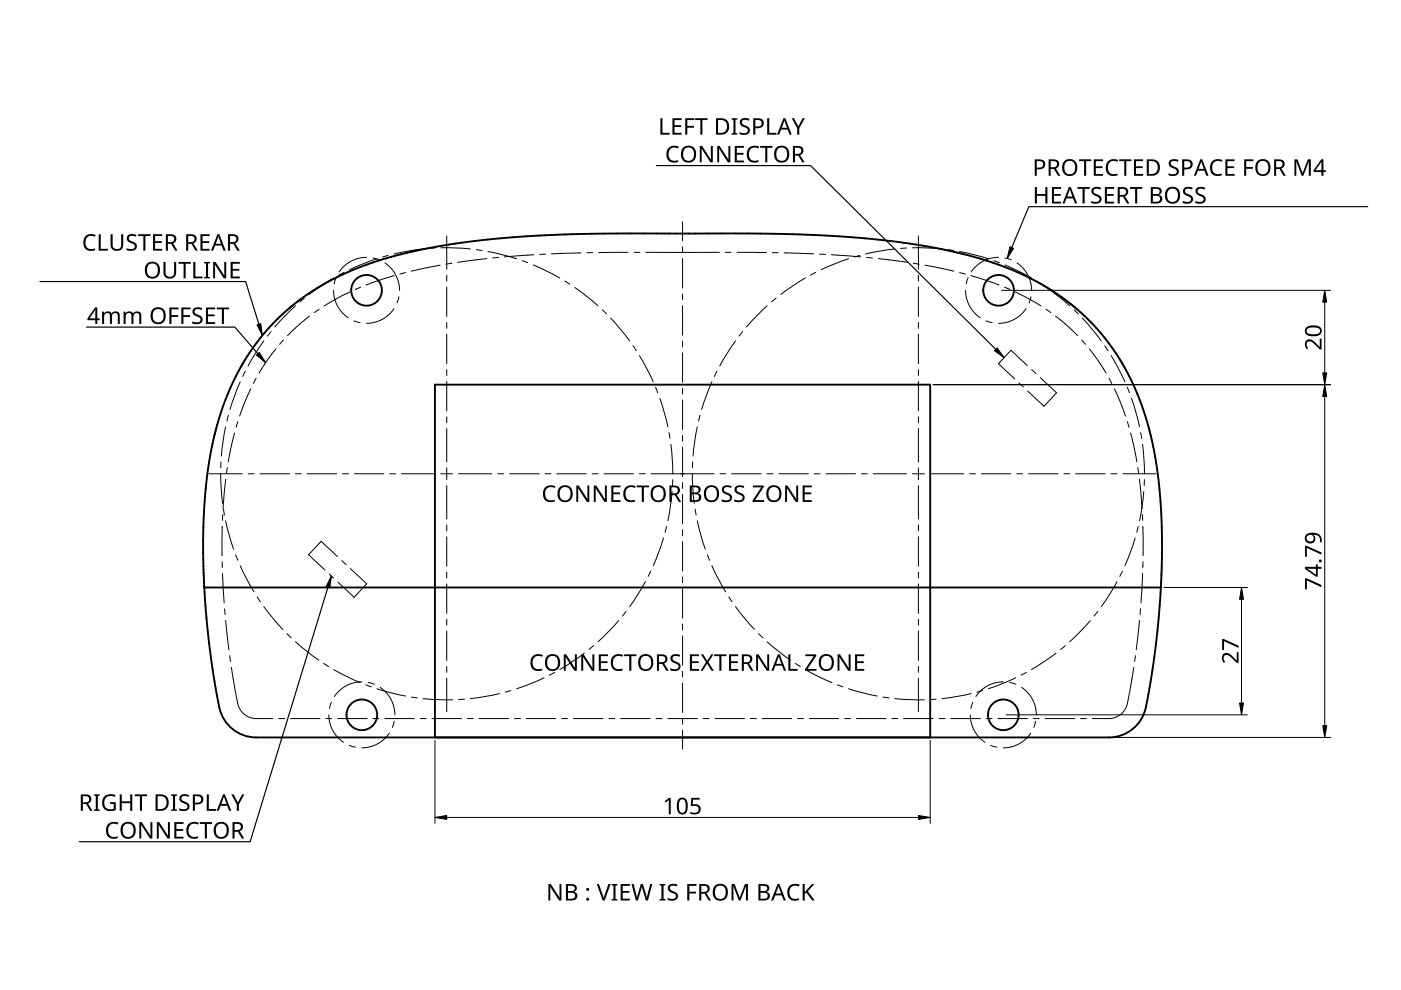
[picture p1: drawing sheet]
<svg xmlns="http://www.w3.org/2000/svg" width="297mm" height="210mm" viewBox="0 0 297 210" stroke-linecap="round" stroke-linejoin="round" font-family="sans-serif">
<g fill="none" stroke="#000" stroke-width=".21">
<path d="M70.7 58.9l-5.2 3.5M71.2 58.9l-.4 1.3M73 57.7l-1.2 .6M77.7 54.6a7 7 0 0 0-5.8 3.1M79.1 54.7l1.3 .4M79.9 54.9l-5.8 2.3M81.6 55.7a7 7 0 0 1 3.1 5.9M82.3 54.2l-1.2 .3M83.6 58.4l-6 2M86 57.8l-1.2 .3M89.7 52.8l-6.2 1M92.2 52.6l-1.2 .1"/>
<path d="M93.3 56.2l-6.1 1.3M93.5 52.5l6.2 .3M95.8 55.8l-1.3 .2M95.8 55.8h.1M101 52.9l1.2 .2M103.2 54.8l-6.2 .8M103.5 53.3l6 1.6M105.7 54.6l-1.2 .1M110.7 55.3l1.2 .4M113.1 56.2l5.6 2.7M113.2 54l-6.3 .5M115.7 53.9h-1.3"/>
<path d="M119.8 59.6l1 .7M123.2 53.6l-6.3 .2M125.7 53.6h-1.3M133.2 53.5h-6.3M134.4 53.5h1.3M136.9 53.5h15.6M155 53.5h-1.2M156.3 53.5h6.2M163.8 53.6h1.2M166.3 53.6l6.2 .2M170.8 58.9l-5.3 3.5M173 57.7l-1.2 .6"/>
<path d="M173.8 53.9h1.2M176.3 54l6.2 .5M179.9 54.9l-5.8 2.3M182.3 54.2l-1.2 .3M183.7 54.6l1.3 .1M186.2 54.8l6.2 .8M189.7 52.8l-6.2 1M192.2 52.6l-1.2 .1M193.5 52.5l6.2 .3M193.7 55.8h.1M193.7 55.8l1.2 .2M196.1 56.2l6.1 1.3"/>
<path d="M201 52.9l1.2 .2M203.5 53.3l6 1.6M203.5 57.8l1.2 .3M205.3 58.9l-.4 1.3M205.9 58.4l5.9 2M210.7 55.3l1.2 .4M211.7 54.6a7 7 0 0 0-5.8 3.1M213.1 56.2l5.6 2.7M213.1 54.7l1.3 .4M215.6 55.7a7 7 0 0 1 3.1 5.9M219.8 59.6l1 .7M52 78.7l-.5 1.1"/>
<path d="M55.9 72.3l-3.3 5.3M57.5 70.3l-.8 1M58.5 74l-1.8 2.3-1.8 2.8M60.1 72.1l-.8 .9M62.6 64.8l-4.3 4.5M64.6 63.2l-1 .8M65.6 67l-2.5 2.1-2.1 2.1M67.7 65.6l-1.1 .7M70.7 61.6a7 7 0 0 0 3.1 5.8M74.2 61.9l-5.5 3M75 68l1.3 .4M76.5 60.9l-1.2 .5"/>
<path d="M83.5 65.4a7 7 0 0 1-5.8 3.2M84.6 62.9l-.4 1.3M121.9 61l4.9 3.8M127.7 65.7l.9 .9M129.5 67.5l4 4.8M134.2 73.3l.7 1M135.6 75.4l2.9 5.6M152 78.7l-.5 1.1M155.9 72.3l-3.3 5.3M157.5 70.3l-.8 1M162.6 64.8l-4.3 4.5M164.6 63.2l-1 .8"/>
<path d="M204.7 61.6a7 7 0 0 0 3.1 5.8M209 68l1.4 .4M213 60.9l1.1 .5M215.2 61.9l5.5 3M217.5 65.4a7 7 0 0 1-5.8 3.2M217.8 77.5l-3.5-3.2-2.6 2.8 3.4 3.2M218.6 62.9l-.4 1.3M218.7 78.3l.9 .9M221.8 65.6l1 .7M221.9 61l4.9 3.8M223.8 67l2.5 2.1 2.2 2.1M227.7 65.7l.9 .9"/>
<path d="M229.3 72.1l.9 .9M229.5 67.5l4 4.8M231 74l1.7 2.3 1.8 2.8M234.2 73.3l.7 1M235.6 75.4l2.9 5.6M46.8 97.9v1.3M47.8 90.5l-.9 6.2M48.2 99.1l-.2 1.3M48.4 88l-.3 1.3M49.7 91.8l-1.3 6.1M50.4 89.4l-.3 1.2M50.9 81l-2.1 5.8"/>
<path d="M53.2 82.4l-2.4 5.8M54.3 80.2l-.6 1.1M139 82.1l.5 1.2M139.9 84.5l1.7 6M141.8 91.7l.3 1.3M142.2 94.2l.4 6.3M146.9 97.9l-.1 1.3M147.8 90.5l-.9 6.2M148.4 88l-.3 1.3M150.9 81l-2.1 5.8M216.1 81.2l.9 .9M220.5 80.1l3.5 3.2-2.7 2.8-3.4-3.2"/>
<path d="M235.1 80.2l.6 1.1M236.3 82.4l2.3 5.8M239 82.1l.5 1.2M239 89.4l.4 1.2M239.7 91.8l1.3 6.1M239.9 84.5l1.7 6M241.2 99.1l.2 1.3M241.8 91.7l.3 1.3M242.2 94.2l.5 6.3M46.8 100.5l.4 6.2M47.1 119.1v1.2M47.1 111.6v6.2"/>
<path d="M47.2 109.1v1.2M47.4 108l.2 1.2M47.8 110.4l1.7 6.1M47.9 101.6l-.6 6.2M50 117.6l.4 1.2M50.9 119.9l2.9 5.6M71.5 118l-3.4-3.2-2.7 2.8 3.5 3.3M72.5 118.9l.9 .8M140.7 114.1l-2.2 5.8M141.3 111.6l-.3 1.3M142.5 104.2l-.9 6.2M142.6 101.7v1.3"/>
<path d="M146.8 100.5l.4 6.2M147.4 108l.2 1.2M147.8 110.4l1.7 6.1M150 117.6l.4 1.2M150.9 119.9l3 5.6M240.7 114.1l-2.2 5.8M241.3 111.6l-.3 1.3M241.6 101.6l.5 6.2M242.2 109.1l.1 1.2M242.3 111.6l.1 6.2M242.3 119.1v1.2M242.5 104.2l-.9 6.2"/>
<path d="M242.6 101.7v1.3M47.2 121.6l.3 6.2M47.6 129.1l.1 1.2M47.8 131.6l.7 6.2M48.7 139l.2 1.3M54.5 126.6l.7 1M55.9 128.6l4 4.8M60.8 134.3l.9 .9M62.6 136.1l5 3.9M69.8 121.7l.9 .9M74.3 120.6l3.4 3.2-2.1 2.3-.5 .5-3.5-3.2M123.9 138.5l-5.2 3.5"/>
<path d="M125.8 136.9l-.9 .8M131.2 131.6l-4.4 4.5M132.7 129.6l-.7 1M136.8 123.3l-3.3 5.3M138 121.1l-.6 1.1M154.5 126.6l.7 1M155.9 128.6l4.1 4.8M160.8 134.3l.9 .9M162.6 136.1l5 3.9M223.9 138.5l-5.2 3.5M225.8 136.9l-.9 .8M231.2 131.6l-4.4 4.5"/>
<path d="M232.7 129.6l-.7 1M236.8 123.3l-3.3 5.3M238 121.1l-.6 1.1M240.7 139l-.1 1.3M241.6 131.6l-.7 6.2M241.8 129.1l-.1 1.2M242.3 121.6l-.4 6.2M49.1 141.5l1.2 6.9a4.1 4.1 0 0 0 4 4h3.5M59.1 152.4h1.2M61.6 152.4h6.2M68.6 140.7l1.1 .6M69.1 152.4h1.2"/>
<path d="M69.7 151.6a7 7 0 0 0 3.1 5.8M70.2 148.9l-.4 1.3M70.7 142l5.7 2.7M71.6 152.4h6.2M74 158l1.3 .4M76.7 144.6a7 7 0 0 0-5.8 3.1M77.5 145.2l1.2 .4M78.1 144.7l1.3 .4M79.1 152.4h1.2M79.9 146l6.1 1.6M80.6 145.7a7 7 0 0 1 3.1 5.9M81.6 152.4h6.2"/>
<path d="M82.5 155.5a7 7 0 0 1-5.8 3.1M83.6 152.9l-.4 1.3M87.2 147.8l1.3 .2M89.1 152.4h1.2M89.7 148.1l6.3 .3M91.6 152.4h6.2M98.5 148.2l-1.3 .1M99.1 152.4h1.2M101.6 152.4h6.2M105.9 147.1l-6.2 1M108.3 146.4l-1.2 .4M109.1 152.4h1.2"/>
<path d="M111.6 152.4h6.2M115.4 143.7l-5.9 2.3M117.6 142.6l-1.1 .6M119.1 152.4h1.2M121.6 152.4h6.2M129.1 152.4h1.2M131.6 152.4h6.2M139.1 152.4h1.2M141.6 152.4h6.2M149.1 152.4h1.2M151.6 152.4h6.2M159.1 152.4h1.2"/>
<path d="M161.6 152.4h6.2M168.6 140.7l1.1 .6M169.1 152.4h1.2M170.8 142l5.6 2.7M171.6 152.4h6.2M177.5 145.2l1.2 .4M179.1 152.4h1.2M179.9 146l6.1 1.6M181.6 152.4h6.2M187.2 147.8l1.3 .2M189.1 152.4h1.2M189.7 148.1l6.3 .3"/>
<path d="M191.6 152.4h6.2M198.5 148.2l-1.3 .1M199.1 152.4h1.2M201.6 152.4h6.2M205.7 151.6a7 7 0 0 0 3.1 5.8M205.9 147.1l-6.2 1M206.3 148.9l-.4 1.3M208.3 146.4l-1.2 .4M209.1 152.4h1.2M210 158l1.4 .4M211.6 152.4h6.2M212.7 144.6a7 7 0 0 0-5.8 3.1"/>
<path d="M214.1 144.7l1.3 .4M215.4 143.7l-5.9 2.3M216.6 145.7a7 7 0 0 1 3.1 5.9M217.6 142.6l-1.1 .6M218.5 155.5a7 7 0 0 1-5.8 3.1M219.1 152.4h1.2M219.6 152.9l-.4 1.3M221.6 152.4h6.2M229.1 152.4h1.2M240.4 141.5l-1.2 6.9a4.1 4.1 0 0 1-4.1 4h-3.5"/>
</g>
<g fill="none" stroke="#000" stroke-width=".4">
<path d="M245.3 99.5l-.7-4.3-1-4.2-1.1-3.9-1.4-3.6-1.6-3.6-1.9-3.3-2-3.1-2.3-3-2.6-2.7-2.6-2.5-2.9-2.2-3.2-2.1-3.3-1.9-3.7-1.7-3.6-1.4-4.3-1.4-4.4-1.1-5-1.1-11-1.5-12.3-1-14.8-.4h-31.5l-14.9 .5-7.7 .6-7.1 .8-6.7 1-6.1 1.4-6.6 1.9-6.1 2.4-5.5 2.9-4.8 3.3-4.4 4-3.8 4.4-3.2 4.9-2.8 5.6-2.1 6.2-1.6 6.4-1 7.2-.5 7.7-.1 9 .5 9.7 1.1 9.8 1.5 9.1a8.4 8.4 0 0 0 8.1 8.1l181.8-.1a8.4 8.4 0 0 0 7.2-8l1.1-6.4 .8-6.5 .6-6.6 .4-6.2 .2-6.3-.1-6.2-.4-5.4-.6-5.2M43.3 124.6h202.8M92.2 156.4v-74.8h105v74.8"/>
<circle cx="77.7" cy="61.6" r="3.3"/>
<circle cx="211.7" cy="61.6" r="3.3"/>
<circle cx="76.7" cy="151.6" r="3.3"/>
<circle cx="212.7" cy="151.6" r="3.3"/>
</g>
<g fill="#000">
<path d="M140 25.1h.5v3.1h1.5v.4h-2zM141.7 31.4a1.95 1.95 0 0 1 2.2-.3l-.1 .4a1.36 1.36 0 0 0-1.7 .1 1.36 1.36 0 0 0-.3 1.7 1.32 1.32 0 0 0 2 .7v.3a1.77 1.77 0 0 1-2.1-.3 1.77 1.77 0 0 1-.3-2.1zM142.6 25.1h1.9v.4h-1.5v1h1.4v.4h-1.4v1.3h1.5v.4h-1.9zM145.3 25.1h1.9v.4h-1.5v1.2h1.4v.4h-1.4v1.5h-.4zM147.4 25.1h2.6v.4h-1.1v3.1h-.4v-3.1h-1.1zM148.4 30.9h.5l1.8 2.9v-2.9h.4v3.5h-.5l-1.9-2.9 .1 2.9h-.4zM152.1 30.9h.5l1.8 2.9v-2.9h.4v3.5h-.5l-1.8-2.9v2.9h-.4zM155.1 25.1h1.3v.2l-.5 .1v2.8l.5 .1v.3h-1.3v-.3l.4-.1v-2.8l-.4-.1zM155.8 30.9h1.9v.4h-1.5v1.1h1.4v.4h-1.4v1.2h1.5v.4h-1.9zM157 25.4a1.65 1.65 0 0 1 1.9-.2l-.1 .4a1.01 1.01 0 0 0-1.5 .2 1.32 1.32 0 0 0 1.2 1 .97 .97 0 0 1 .4 1.3 .97 .97 0 0 1-1.1 .5l-1-.2v-.4a1.24 1.24 0 0 0 1.8-.2 1.06 1.06 0 0 0-1.1-.9 .95 .95 0 0 1-.5-1.5zM158.8 31.4a1.95 1.95 0 0 1 2.2-.3l-.2 .4a1.36 1.36 0 0 0-1.7 .1 1.36 1.36 0 0 0-.2 1.7 1.32 1.32 0 0 0 1.9 .7v.3a1.77 1.77 0 0 1-2.1-.3 1.77 1.77 0 0 1-.3-2.1zM162.7 25.1h.4v3.1h1.5v.4h-1.9z"/>
<path d="M161.2 30.9h2.6v.4h-1.1v3.1h-.5v-3.1h-1zM167.9 25.1h.4l.9 1.7 1-1.7h.4l-1.1 2.1v1.4h-.5v-1.4zM228.8 33.8h2.6v.4h-1.1v3.1h-.5v-3.1h-1zM231.9 33.8h1.9v.4h-1.5v1.1h1.5v.3h-1.5v1.3h1.5v.4h-1.9zM234.9 34.2a1.95 1.95 0 0 1 2.2-.3l-.2 .4a1.36 1.36 0 0 0-1.7 .2 1.36 1.36 0 0 0-.2 1.6 1.32 1.32 0 0 0 1.9 .7v.4a1.77 1.77 0 0 1-2-.3 1.77 1.77 0 0 1-.3-2.1zM237.3 33.8h2.6v.4h-1.1v3.1h-.4v-3.1h-1.1zM240.4 33.8h2v.4h-1.5v1.1h1.4v.3h-1.4v1.3h1.5v.4h-2zM248 34.1a1.65 1.65 0 0 1 1.9-.2l-.2 .4a1.01 1.01 0 0 0-1.5 .2 1.31 1.31 0 0 0 1.3 1 .97 .97 0 0 1 .4 1.3 .97 .97 0 0 1-1.2 .5l-1-.1v-.5a1.24 1.24 0 0 0 1.8-.2 1.06 1.06 0 0 0-1-.9 .95 .95 0 0 1-.5-1.5zM257 34.2a1.95 1.95 0 0 1 2.2-.3l-.2 .4a1.36 1.36 0 0 0-1.7 .2 1.36 1.36 0 0 0-.2 1.6 1.32 1.32 0 0 0 1.9 .7v.4a1.77 1.77 0 0 1-2-.3 1.77 1.77 0 0 1-.3-2.1zM259.8 33.8h2v.4h-1.6v1.1h1.5v.3h-1.5v1.3h1.6v.4h-2zM263.8 33.8h1.9v.4h-1.5v1.2h1.4v.4h-1.4v1.5h-.4zM274.4 33.8h.7l1.1 2.8 1.1-2.8h.6v3.5h-.4v-3.1l-1.2 3.1h-.3l-1.2-3.1v3.1h-.4z"/>
<path d="M18.1 50.1a1.95 1.95 0 0 1 2.2-.3l-.2 .4a1.36 1.36 0 0 0-1.7 .1 1.36 1.36 0 0 0-.2 1.7 1.32 1.32 0 0 0 2 .7v.4a1.77 1.77 0 0 1-2.1-.4 1.77 1.77 0 0 1-.3-2zM20.9 49.7h.5v3.1h1.5v.3h-2zM23.4 49.7h.5v2.2a.9 .9 0 0 0 .9 .9 .9 .9 0 0 0 .9-.9v-2.2h.4v2.2a1.34 1.34 0 0 1-1.3 1.3 1.34 1.34 0 0 1-1.4-1.3zM27 50a1.65 1.65 0 0 1 1.9-.2l-.1 .4a1.01 1.01 0 0 0-1.5 .2 1.31 1.31 0 0 0 1.2 1 .97 .97 0 0 1 .4 1.2 .97 .97 0 0 1-1.1 .6l-1-.2v-.4a1.24 1.24 0 0 0 1.8-.2 1.06 1.06 0 0 0-1.1-1 .95 .95 0 0 1-.5-1.4zM29.3 49.7h2.6v.3h-1.1v3.1h-.4v-3.1h-1.1zM32.4 49.7h2v.3h-1.5v1.1h1.4v.4h-1.4v1.3h1.5v.3h-2zM34.7 55.5h.4v2.3a.9 .9 0 0 0 .9 .9 .9 .9 0 0 0 .9-.9v-2.3h.4v2.3a1.35 1.35 0 0 1-1.3 1.3 1.35 1.35 0 0 1-1.3-1.3zM37.8 55.5h2.7v.4h-1.1v3.1h-.5v-3.1h-1.1zM41 55.5h.4v3.1h1.5v.4h-1.9zM42.5 49.7h1.9v.3h-1.5v1.1h1.5v.4h-1.5v1.3h1.5v.3h-1.9zM43.3 55.5h1.2v.3l-.4 .1v2.8l.4 .1v.2h-1.2v-.2l.4-.1v-2.8l-.4-.1zM45.2 55.5h.5l1.9 2.9-.1-2.9h.5v3.5h-.6l-1.8-2.9v2.9h-.4z"/>
<path d="M48.9 55.5h2v.4h-1.6v1.1h1.5v.4h-1.5v1.2h1.6v.4h-2zM219.4 39.7h.4v1.4h1.8v-1.4h.5v3.4h-.5v-1.6h-1.8v1.6h-.4zM223 39.7h2v.3h-1.5v1.1h1.4v.4h-1.4v1.3h1.5v.3h-2zM228.4 39.7h2.6v.3h-1v3.1h-.5v-3.1h-1.1zM231.6 40a1.65 1.65 0 0 1 1.9-.2l-.2 .4a1.01 1.01 0 0 0-1.5 .2 1.31 1.31 0 0 0 1.3 1 .97 .97 0 0 1 .4 1.2 .97 .97 0 0 1-1.2 .6l-1-.2v-.4a1.24 1.24 0 0 0 1.8-.2 1.06 1.06 0 0 0-1-1 .95 .95 0 0 1-.5-1.4zM234.3 39.7h1.9v.3h-1.5v1.1h1.4v.4h-1.4v1.3h1.5v.3h-1.9zM239.6 39.7h2.6v.3h-1.1v3.1h-.4v-3.1h-1.1zM251 40a1.65 1.65 0 0 1 1.9-.2l-.2 .4a1.01 1.01 0 0 0-1.4 .2 1.31 1.31 0 0 0 1.2 1 .97 .97 0 0 1 .4 1.2 .97 .97 0 0 1-1.2 .6l-.9-.2v-.4a1.24 1.24 0 0 0 1.7-.2 1.06 1.06 0 0 0-1-1 .95 .95 0 0 1-.5-1.4zM253.7 40a1.65 1.65 0 0 1 1.9-.2l-.2 .4a1.01 1.01 0 0 0-1.5 .2 1.31 1.31 0 0 0 1.3 1 .97 .97 0 0 1 .4 1.2 .97 .97 0 0 1-1.2 .6l-1-.2v-.4a1.24 1.24 0 0 0 1.8-.2 1.06 1.06 0 0 0-1-1 .95 .95 0 0 1-.5-1.4zM21.6 66.1h.4l.1 .3a.99 .99 0 0 1 1.6 .1 .93 .93 0 0 1 1-.4 .93 .93 0 0 1 .7 .9v1.7h-.4v-1.7a.64 .64 0 0 0-.8-.6 .64 .64 0 0 0-.5 .8v1.5h-.4v-1.7a.66 .66 0 0 0-.8-.6 .66 .66 0 0 0-.4 .9v1.4h-.5zM26.2 66.1h.4v.3a.99 .99 0 0 1 1.6 .1 .93 .93 0 0 1 1.1-.4 .93 .93 0 0 1 .7 .9v1.7h-.5v-1.7a.64 .64 0 0 0-.7-.6 .64 .64 0 0 0-.5 .8v1.5h-.4v-1.7a.66 .66 0 0 0-.9-.6 .66 .66 0 0 0-.4 .9v1.4h-.4zM35.9 65.2h2v.4h-1.5v1.2h1.4v.4h-1.4v1.5h-.5z"/>
<path d="M38.4 65.2h2v.4h-1.5v1.2h1.4v.4h-1.4v1.5h-.5zM41 65.5a1.65 1.65 0 0 1 1.9-.2l-.2 .4a1.01 1.01 0 0 0-1.4 .2 1.31 1.31 0 0 0 1.2 1.1 .97 .97 0 0 1 .4 1.2 .97 .97 0 0 1-1.2 .5l-.9-.1v-.5a1.24 1.24 0 0 0 1.7-.2 1.06 1.06 0 0 0-1-.9 .95 .95 0 0 1-.5-1.5zM43.7 65.2h1.9v.4h-1.5v1.1h1.4v.4h-1.4v1.2h1.5v.4h-1.9zM46 65.2h2.6v.4h-1.1v3.1h-.5v-3.1h-1zM276.9 72.2a1.5 1.5 0 0 1 2.2 .6l.7 .8v-1.8h.4v2.3h-.4l-1.1-1.1a.98 .98 0 0 0-1.6-.3l-.1 .5 .4 .6-.3 .3a1.47 1.47 0 0 1-.2-1.9zM115.6 103.4a1.95 1.95 0 0 1 2.1-.3l-.1 .4a1.36 1.36 0 0 0-1.7 .1 1.36 1.36 0 0 0-.2 1.7 1.32 1.32 0 0 0 1.9 .6v.4a1.77 1.77 0 0 1-2.1-.3 1.77 1.77 0 0 1-.3-2.1zM122.2 102.9h.5l1.9 2.9-.1-2.9h.4v3.5h-.5l-1.8-2.9v2.9h-.4zM125.9 102.9h.5l1.9 2.9-.1-2.9h.5v3.5h-.6l-1.8-2.9v2.9h-.4zM129.6 102.9h2v.4h-1.6v1.1h1.5v.4h-1.5v1.2h1.6v.4h-2zM132.6 103.4a1.95 1.95 0 0 1 2.2-.3l-.2 .4a1.36 1.36 0 0 0-1.7 .1 1.36 1.36 0 0 0-.2 1.7 1.32 1.32 0 0 0 1.9 .6v.4a1.77 1.77 0 0 1-2-.3 1.77 1.77 0 0 1-.3-2.1zM135 102.9h2.6v.4h-1.1v3.1h-.4v-3.1h-1.1zM153.2 103.3a1.65 1.65 0 0 1 1.9-.2l-.1 .4a1.01 1.01 0 0 0-1.5 .2 1.31 1.31 0 0 0 1.2 1 .97 .97 0 0 1 .4 1.2 .97 .97 0 0 1-1.1 .6l-1-.2v-.4a1.24 1.24 0 0 0 1.8-.2 1.06 1.06 0 0 0-1.1-1 .95 .95 0 0 1-.5-1.4z"/>
<path d="M155.9 103.3a1.65 1.65 0 0 1 1.9-.2l-.1 .4a1.01 1.01 0 0 0-1.5 .2 1.31 1.31 0 0 0 1.2 1 .97 .97 0 0 1 .4 1.2 .97 .97 0 0 1-1.2 .6l-.9-.2v-.4a1.24 1.24 0 0 0 1.7-.2 1.06 1.06 0 0 0-1-1 .95 .95 0 0 1-.5-1.4zM159.6 102.9h2.3v.4l-1.8 2.7h1.9v.4h-2.4v-.3l1.8-2.8h-1.8zM166.5 102.9h.5l1.8 2.9v-2.9h.4v3.5h-.5l-1.9-2.9 .1 2.9h-.4zM170.2 102.9h1.9v.4h-1.5v1.1h1.4v.4h-1.4v1.2h1.5v.4h-1.9zM276.7 115.7h.3l3.2 1.4v.5l-3.1-1.4v1.9h-.4zM112.9 139.2a1.95 1.95 0 0 1 2.2-.3l-.2 .4a1.36 1.36 0 0 0-1.7 .1 1.36 1.36 0 0 0-.2 1.7 1.32 1.32 0 0 0 2 .6v.4a1.77 1.77 0 0 1-2.1-.3 1.77 1.77 0 0 1-.3-2.1zM129.9 139.2a1.95 1.95 0 0 1 2.2-.3l-.1 .4a1.36 1.36 0 0 0-1.7 .1 1.36 1.36 0 0 0-.3 1.7 1.32 1.32 0 0 0 2 .6v.4a1.77 1.77 0 0 1-2.1-.3 1.77 1.77 0 0 1-.3-2.1zM259.3 138.7a1.5 1.5 0 0 1 2.2 .6l.7 .7v-1.7h.4v2.3h-.4l-1.1-1.1a.98 .98 0 0 0-1.6-.3v.5l.3 .6-.3 .3a1.47 1.47 0 0 1-.2-1.9zM259.1 135.5h.3l3.2 1.4v.5l-3.1-1.5v1.9h-.4zM276.7 122.6h.3l3.2 1.4v.5l-3.1-1.4v1.8h-.4zM119.5 138.7h.5l1.9 2.9v-2.9h.4v3.5h-.5l-1.9-2.9v2.9h-.4zM123.2 138.7h.6l1.8 2.9v-2.9h.4v3.5h-.5l-1.9-2.9 .1 2.9h-.5z"/>
<path d="M127 138.7h1.9v.4h-1.5v1.1h1.4v.4h-1.4v1.2h1.5v.4h-1.9zM132.3 138.7h2.6v.4h-1v3.1h-.5v-3.1h-1.1zM142.3 139.1a1.65 1.65 0 0 1 1.9-.2l-.1 .4a1.01 1.01 0 0 0-1.5 .2 1.31 1.31 0 0 0 1.2 1 .97 .97 0 0 1 .4 1.2 .97 .97 0 0 1-1.1 .6l-1-.2v-.4a1.24 1.24 0 0 0 1.7-.3 1.06 1.06 0 0 0-1-.9 .95 .95 0 0 1-.5-1.4zM146.3 138.7h1.9v.4h-1.5v1.1h1.4v.4h-1.4v1.2h1.5v.4h-1.9zM148.6 138.7h.5l.8 1.4 .9-1.4h.5l-1.1 1.7 1.2 1.8h-.5l-1-1.5-.9 1.5h-.5l1.2-1.8zM151.4 138.7h2.6v.4h-1v3.1h-.5v-3.1h-1.1zM154.6 138.7h1.9v.4h-1.5v1.1h1.4v.4h-1.4v1.2h1.5v.4h-1.9zM160.3 138.7h.5l1.9 2.9v-2.9h.4v3.5h-.5l-1.9-2.9v2.9h-.4zM167.1 138.7h.5v3.1h1.5v.4h-2zM170.7 138.7h2.4v.4l-1.9 2.7h1.9v.4h-2.4v-.3l1.8-2.8h-1.8zM177.6 138.7h.5l1.8 2.9v-2.9h.4v3.5h-.5l-1.8-2.9v2.9h-.4zM181.3 138.7h1.9v.4h-1.5v1.1h1.4v.4h-1.4v1.2h1.5v.4h-1.9z"/>
<path d="M19.9 168.4h1.3v.3l-.5 .1v2.8l.5 .1v.2h-1.3v-.2l.4-.1v-2.8l-.4-.1zM22.1 168.9a2.23 2.23 0 0 1 2.4-.3l-.2 .4a1.44 1.44 0 0 0-2.2 1 1.44 1.44 0 0 0 2 1.5v-1h-.8v-.4h1.2v1.7l-.2 .1a1.86 1.86 0 0 1-2.4-.6 1.86 1.86 0 0 1 .2-2.4zM22.9 174.7a1.95 1.95 0 0 1 2.2-.2l-.2 .3a1.36 1.36 0 0 0-1.6 .2 1.36 1.36 0 0 0-.3 1.6 1.32 1.32 0 0 0 2 .7v.4a1.77 1.77 0 0 1-2.1-.3 1.77 1.77 0 0 1-.3-2.1zM25.4 168.4h.4v1.5h1.8v-1.5h.4v3.5h-.4v-1.6h-1.8v1.6h-.4zM28.6 168.4h2.6v.4h-1.1v3.1h-.4v-3.1h-1.1zM29.5 174.3h.6l1.8 2.9v-2.9h.4v3.5h-.5l-1.9-2.9v2.9h-.4zM33.3 174.3h.5l1.8 2.9v-2.9h.4v3.5h-.5l-1.9-2.9 .1 2.9h-.4zM36.3 168.4h1.2v.3l-.4 .1v2.8l.4 .1v.2h-1.2v-.2l.4-.1v-2.8l-.4-.1zM37 174.3h1.9v.4h-1.5v1.1h1.4v.4h-1.4v1.2h1.5v.4h-1.9zM38.2 168.8a1.65 1.65 0 0 1 1.9-.2l-.1 .4a1.01 1.01 0 0 0-1.5 .2 1.31 1.31 0 0 0 1.2 1 .97 .97 0 0 1 .4 1.2 .97 .97 0 0 1-1.2 .6l-.9-.2v-.4a1.24 1.24 0 0 0 1.7-.3 1.06 1.06 0 0 0-1-.9 .95 .95 0 0 1-.5-1.4zM39.9 174.7a1.95 1.95 0 0 1 2.2-.2l-.1 .3a1.36 1.36 0 0 0-1.7 .2 1.36 1.36 0 0 0-.3 1.6 1.32 1.32 0 0 0 2 .7v.4a1.77 1.77 0 0 1-2.1-.3 1.77 1.77 0 0 1-.3-2.1zM43.8 168.4h.5v3.1h1.5v.4h-2z"/>
<path d="M42.3 174.3h2.7v.4h-1.1v3.1h-.5v-3.1h-1.1zM49 168.4h.5l.9 1.7 .9-1.7h.5l-1.2 2.2v1.3h-.4v-1.3zM140.9 169.9l1-.7h.3v3.4h-.4v-3l-.7 .6zM146.6 169.2h1.7v.4h-1.4v1a1.17 1.17 0 0 1 1.7 .9 1.17 1.17 0 0 1-1.6 1.2l-.6-.2v-.4a1.03 1.03 0 0 0 1 .3 1.03 1.03 0 0 0 .7-.8 .93 .93 0 0 0-1.4-.7l-.3-.1zM116.3 187.4h.5l1.8 2.9v-2.9h.4v3.5h-.5l-1.8-2.9v2.9h-.4zM126.5 187.4h.5l1 3 1-3h.5l-1.3 3.5h-.4zM129.7 187.4h1.2v.3l-.4 .1v2.8l.4 .1v.2h-1.2v-.2l.4-.1v-2.8l-.4-.1zM131.6 187.4h1.9v.4h-1.5v1.1h1.4v.4h-1.4v1.2h1.5v.4h-1.9zM133.9 187.4h.4l.8 3 .8-3h.4l.8 3 .7-3h.5l-.9 3.5h-.5l-.8-3-.8 3h-.5zM139.8 187.4h1.3v.3l-.4 .1v2.8l.4 .1v.2h-1.3v-.2l.4-.1v-2.8l-.4-.1zM141.8 187.8a1.65 1.65 0 0 1 1.9-.2l-.2 .4a1.01 1.01 0 0 0-1.5 .2 1.31 1.31 0 0 0 1.3 1 .97 .97 0 0 1 .4 1.2 .97 .97 0 0 1-1.2 .6l-1-.2v-.4a1.24 1.24 0 0 0 1.8-.2 1.06 1.06 0 0 0-1-1 .95 .95 0 0 1-.5-1.4zM145.7 187.4h2v.4h-1.5v1.3h1.4v.3h-1.4v1.5h-.5z"/>
<path d="M155.1 187.4h.6l1.1 2.9 1.1-2.9h.7v3.5h-.5l.1-3-1.2 3h-.4l-1.1-3v3h-.4zM167.4 187.9a1.95 1.95 0 0 1 2.2-.3l-.2 .4a1.36 1.36 0 0 0-1.7 .1 1.36 1.36 0 0 0-.2 1.7 1.32 1.32 0 0 0 1.9 .6v.4a1.77 1.77 0 0 1-2.1-.3 1.77 1.77 0 0 1-.3-2.1zM170.2 187.4h.4v1.8l1.6-1.8h.5l-1.4 1.6 1.4 1.9h-.5l-1.2-1.6-.4 .3v1.3h-.4z"/>
<path d="M144.8 31.4a1.7 1.7 0 0 1 2.2-.2 1.7 1.7 0 0 1 .5 2.1 1.64 1.64 0 0 1-2 1.1 1.64 1.64 0 0 1-1.1-2.1zM145.2 31.6a1.56 1.56 0 0 0 .5 2.5 1.35 1.35 0 0 0 1.3-.6 1.35 1.35 0 0 0 .1-1.4 1.14 1.14 0 0 0-1.9-.5z"/>
<path d="M151.8 25.1h1.1a1.74 1.74 0 0 1 1.7 1.8 1.74 1.74 0 0 1-1.8 1.7h-1zM152.2 25.4v2.8h.5a1.37 1.37 0 0 0 1.4-1.3 1.37 1.37 0 0 0-1.3-1.5z"/>
<path d="M159.7 25.1h.9a1.1 1.1 0 0 1 1.3 1.1 1.1 1.1 0 0 1-1.4 1h-.4v1.4h-.4zM160.1 25.4v1.4a.94 .94 0 0 0 1.4-.7 .7 .7 0 0 0-.9-.7z"/>
<path d="M164.5 31.4a1.7 1.7 0 0 1 2.2-.2 1.7 1.7 0 0 1 .6 2.1 1.64 1.64 0 0 1-2.1 1.1 1.64 1.64 0 0 1-1-2.1zM165 31.6a1.56 1.56 0 0 0 .5 2.5 1.35 1.35 0 0 0 1.3-.6 1.35 1.35 0 0 0 0-1.4 1.14 1.14 0 0 0-1.8-.5z"/>
<path d="M166.1 25.1h.4l1.4 3.5h-.5l-.4-1.1h-1.4l-.4 1.1h-.5zM166.3 25.5l-.6 1.6h1.2z"/>
<path d="M168.1 30.9h1a1 1 0 0 1 1.2 .7 1 1 0 0 1-.7 1.3l1 1.5h-.5l-.9-1.4h-.6v1.4h-.5zM168.6 31.3v1.3h.5a.67 .67 0 0 0 .8-.6 .67 .67 0 0 0-.8-.7z"/>
<path d="M219.4 33.8h.9a1.1 1.1 0 0 1 1.3 1.1 1.1 1.1 0 0 1-1.4 1h-.4v1.4h-.4zM219.8 34.2v1.3a.94 .94 0 0 0 1.4-.7 .7 .7 0 0 0-.9-.6z"/>
<path d="M222.3 33.8h1a1 1 0 0 1 1.2 .7 1 1 0 0 1-.6 1.2l.9 1.6h-.5l-.8-1.5h-.7v1.5h-.5zM222.8 34.2v1.3h.5a.67 .67 0 0 0 .8-.7 .67 .67 0 0 0-.8-.6z"/>
<path d="M225.6 34.2a1.7 1.7 0 0 1 2.2-.2 1.7 1.7 0 0 1 .6 2.1 1.64 1.64 0 0 1-2.1 1.1 1.64 1.64 0 0 1-1.1-2.1zM226 34.4a1.56 1.56 0 0 0 .5 2.5 1.35 1.35 0 0 0 1.3-.6 1.35 1.35 0 0 0 .1-1.4 1.14 1.14 0 0 0-1.9-.5z"/>
<path d="M244 39.7h1a.94 .94 0 0 1 1 .2 .94 .94 0 0 1 .2 1l-.6 .4a.95 .95 0 0 1 .8 1.2 .95 .95 0 0 1-1.2 .6h-1.2zM244.4 41.5v1.3h.7a.66 .66 0 0 0 .9-.7 .66 .66 0 0 0-.9-.6zM244.4 40v1.1h.7a.6 .6 0 0 0 .8-.6 .6 .6 0 0 0-.9-.5z"/>
<path d="M243.1 33.8h1.1a1.74 1.74 0 0 1 1.7 1.8 1.74 1.74 0 0 1-1.8 1.7h-1zM243.6 34.2v2.7h.4a1.37 1.37 0 0 0 1.5-1.3 1.37 1.37 0 0 0-1.4-1.4z"/>
<path d="M250.6 33.8h1a1.1 1.1 0 0 1 1.3 1.1 1.1 1.1 0 0 1-1.4 1h-.4v1.4h-.5zM251.1 34.2v1.3a.94 .94 0 0 0 1.3-.7 .7 .7 0 0 0-.9-.6z"/>
<path d="M254.5 33.8h.4l1.3 3.5h-.4l-.4-1.1h-1.4l-.4 1.1h-.5zM254.7 34.2l-.6 1.6h1.1z"/>
<path d="M266.6 34.2a1.7 1.7 0 0 1 2.1-.2 1.7 1.7 0 0 1 .6 2.1 1.64 1.64 0 0 1-2.1 1.1 1.64 1.64 0 0 1-1-2.1zM267 34.4a1.56 1.56 0 0 0 .5 2.5 1.35 1.35 0 0 0 1.3-.6 1.35 1.35 0 0 0 0-1.4 1.14 1.14 0 0 0-1.8-.5z"/>
<path d="M270.1 33.8h1a1 1 0 0 1 1.2 .7 1 1 0 0 1-.6 1.2l.9 1.6h-.5l-.8-1.5h-.7v1.5h-.5zM270.6 34.2v1.3h.5a.67 .67 0 0 0 .8-.7 .67 .67 0 0 0-.8-.6z"/>
<path d="M280.1 33.8h.5v2.3h.5v.4h-.5v.8h-.4v-.8h-1.7v-.4zM280.2 34.2l-1.3 1.9h1.3z"/>
<path d="M31.1 56a1.7 1.7 0 0 1 2.2-.2 1.7 1.7 0 0 1 .6 2.1 1.64 1.64 0 0 1-2.1 1.1 1.64 1.64 0 0 1-1.1-2.1zM31.5 56.1a1.56 1.56 0 0 0 .6 2.6 1.35 1.35 0 0 0 1.2-.6 1.35 1.35 0 0 0 .1-1.4 1.14 1.14 0 0 0-1.9-.6z"/>
<path d="M35.2 49.7h.9a1 1 0 0 1 1.2 .6 1 1 0 0 1-.6 1.3l.9 1.5h-.5l-.8-1.4h-.7v1.4h-.4zM35.6 50v1.3h.5a.67 .67 0 0 0 .8-.6 .67 .67 0 0 0-.8-.7z"/>
<path d="M39.5 49.7h.9a1 1 0 0 1 1.3 .6 1 1 0 0 1-.7 1.3l1 1.5h-.6l-.8-1.4h-.7v1.4h-.4zM39.9 50v1.3h.5a.67 .67 0 0 0 .8-.6 .67 .67 0 0 0-.8-.7z"/>
<path d="M46.1 49.6h.4l1.4 3.5h-.5l-.4-1h-1.4l-.4 1h-.5zM46.3 50.1l-.6 1.6h1.2z"/>
<path d="M48.3 49.7h1a1 1 0 0 1 1.2 .6 1 1 0 0 1-.6 1.3l.9 1.5h-.5l-.8-1.4h-.7v1.4h-.5zM48.8 50v1.3h.5a.67 .67 0 0 0 .8-.6 .67 .67 0 0 0-.8-.7z"/>
<path d="M226.6 39.6h.4l1.4 3.5h-.5l-.4-1h-1.4l-.4 1h-.4zM226.8 40.1l-.5 1.6h1.1z"/>
<path d="M237 39.7h.9a1 1 0 0 1 1.3 .6 1 1 0 0 1-.7 1.3l1 1.5h-.6l-.8-1.4h-.7v1.4h-.4zM237.4 40v1.3h.5a.67 .67 0 0 0 .8-.6 .67 .67 0 0 0-.8-.7z"/>
<path d="M247.4 40.1a1.7 1.7 0 0 1 2.2-.2 1.7 1.7 0 0 1 .5 2.1 1.64 1.64 0 0 1-2 1.1 1.64 1.64 0 0 1-1.1-2.1zM247.8 40.3a1.56 1.56 0 0 0 .5 2.5 1.35 1.35 0 0 0 1.3-.6 1.35 1.35 0 0 0 .1-1.4 1.14 1.14 0 0 0-1.9-.5z"/>
<path d="M20.2 65.2h.4v2.3h.5v.4h-.5v.8h-.4v-.8h-1.7v-.4zM20.2 65.6l-1.2 1.9h1.2z"/>
<path d="M32.3 65.6a1.7 1.7 0 0 1 2.2-.2 1.7 1.7 0 0 1 .6 2.1 1.64 1.64 0 0 1-2.1 1.2 1.64 1.64 0 0 1-1.1-2.2zM32.8 65.8a1.56 1.56 0 0 0 .5 2.5 1.35 1.35 0 0 0 1.3-.6 1.35 1.35 0 0 0 0-1.4 1.14 1.14 0 0 0-1.8-.5z"/>
<path d="M276.9 69.5a2.6 2.6 0 0 1 3.2 .1 1.22 1.22 0 0 1-.2 1.3 1.22 1.22 0 0 1-1.2 .4 1.53 1.53 0 0 1-2-1zM277.2 69.7a.75 .75 0 0 0 0 .9 .75 .75 0 0 0 .9 .3l1-.1a.69 .69 0 0 0 .8-.7 .69 .69 0 0 0-.8-.6h-1.3z"/>
<path d="M118.6 103.4a1.7 1.7 0 0 1 2.2-.2 1.7 1.7 0 0 1 .6 2.1 1.64 1.64 0 0 1-2.1 1.1 1.64 1.64 0 0 1-1.1-2.1zM119 103.5a1.56 1.56 0 0 0 .5 2.6 1.35 1.35 0 0 0 1.3-.6 1.35 1.35 0 0 0 .1-1.4 1.14 1.14 0 0 0-1.9-.6z"/>
<path d="M138.4 103.4a1.7 1.7 0 0 1 2.1-.2 1.7 1.7 0 0 1 .6 2.1 1.64 1.64 0 0 1-2.1 1.1 1.64 1.64 0 0 1-1-2.1zM138.8 103.5a1.56 1.56 0 0 0 .5 2.6 1.35 1.35 0 0 0 1.3-.6 1.35 1.35 0 0 0 0-1.4 1.14 1.14 0 0 0-1.8-.6z"/>
<path d="M141.9 102.9h1a1 1 0 0 1 1.2 .7 1 1 0 0 1-.6 1.3l.9 1.5h-.5l-.8-1.4h-.7v1.4h-.5zM142.4 103.3v1.3h.5a.67 .67 0 0 0 .8-.7 .67 .67 0 0 0-.8-.6z"/>
<path d="M146.2 102.9h1a.94 .94 0 0 1 1.1 .2 .94 .94 0 0 1 .2 1.1l-.6 .4a.95 .95 0 0 1 .8 1.1 .95 .95 0 0 1-1.2 .7h-1.3zM146.7 104.8v1.3h.7a.66 .66 0 0 0 .8-.7 .66 .66 0 0 0-.8-.6zM146.7 103.3v1.1h.6a.6 .6 0 0 0 .8-.6 .6 .6 0 0 0-.8-.5z"/>
<path d="M149.7 103.4a1.7 1.7 0 0 1 2.1-.2 1.7 1.7 0 0 1 .6 2.1 1.64 1.64 0 0 1-2.1 1.1 1.64 1.64 0 0 1-1-2.1zM150.1 103.5a1.56 1.56 0 0 0 .5 2.6 1.35 1.35 0 0 0 1.3-.6 1.35 1.35 0 0 0 0-1.4 1.14 1.14 0 0 0-1.8-.6z"/>
<path d="M162.9 103.4a1.7 1.7 0 0 1 2.2-.2 1.7 1.7 0 0 1 .5 2.1 1.64 1.64 0 0 1-2.1 1.1 1.64 1.64 0 0 1-1-2.1zM163.3 103.5a1.56 1.56 0 0 0 .5 2.6 1.35 1.35 0 0 0 1.3-.6 1.35 1.35 0 0 0 .1-1.4 1.14 1.14 0 0 0-1.9-.6z"/>
<path d="M276.9 113.4a2.18 2.18 0 0 1 3.3 .6v1h-.4a1.16 1.16 0 0 0-.2-1.2 1.16 1.16 0 0 0-1.1-.4 1.08 1.08 0 0 1 .1 1.6 1.08 1.08 0 0 1-1.6-.1 1.16 1.16 0 0 1-.1-1.5zM277 114.1a.76 .76 0 0 0 1.5 0 .76 .76 0 0 0-1.5 0z"/>
<path d="M276.7 120.2h2.3v-.5h.4v.5h.8v.4h-.8v1.7h-.4l-2.3-1.7zM277.1 120.6l1.9 1.3v-1.3z"/>
<path d="M116 139.1a1.7 1.7 0 0 1 2.1-.1 1.7 1.7 0 0 1 .6 2 1.64 1.64 0 0 1-2.1 1.2 1.64 1.64 0 0 1-1-2.1zM116.4 139.3a1.56 1.56 0 0 0 .5 2.6 1.35 1.35 0 0 0 1.3-.6 1.35 1.35 0 0 0 0-1.4 1.14 1.14 0 0 0-1.8-.6z"/>
<path d="M135.7 139.1a1.7 1.7 0 0 1 2.2-.1 1.7 1.7 0 0 1 .6 2 1.64 1.64 0 0 1-2.1 1.2 1.64 1.64 0 0 1-1.1-2.1zM136.1 139.3a1.56 1.56 0 0 0 .5 2.6 1.35 1.35 0 0 0 1.3-.6 1.35 1.35 0 0 0 .1-1.4 1.14 1.14 0 0 0-1.9-.6z"/>
<path d="M139.3 138.7h.9a1 1 0 0 1 1.3 .7 1 1 0 0 1-.7 1.3l1 1.5h-.5l-.9-1.4h-.7v1.4h-.4zM139.7 139.1v1.3h.5a.67 .67 0 0 0 .9-.7 .67 .67 0 0 0-.9-.6z"/>
<path d="M157.3 138.7h.9a1 1 0 0 1 1.3 .7 1 1 0 0 1-.7 1.3l1 1.5h-.5l-.9-1.4h-.7v1.4h-.4zM157.7 139.1v1.3h.5a.67 .67 0 0 0 .9-.7 .67 .67 0 0 0-.9-.6z"/>
<path d="M164.9 138.7h.4l1.4 3.5h-.5l-.4-1.1h-1.4l-.4 1.1h-.4zM165.1 139.2l-.5 1.6h1.1z"/>
<path d="M174 139.1a1.7 1.7 0 0 1 2.2-.1 1.7 1.7 0 0 1 .5 2 1.64 1.64 0 0 1-2 1.2 1.64 1.64 0 0 1-1.1-2.1zM174.4 139.3a1.56 1.56 0 0 0 .5 2.6 1.35 1.35 0 0 0 1.3-.6 1.35 1.35 0 0 0 .1-1.4 1.14 1.14 0 0 0-1.9-.6z"/>
<path d="M17.1 168.4h1a1 1 0 0 1 1.2 .7 1 1 0 0 1-.6 1.3l.9 1.5h-.5l-.8-1.4h-.7v1.4h-.5zM17.6 168.8v1.3h.5a.67 .67 0 0 0 .8-.7 .67 .67 0 0 0-.8-.6z"/>
<path d="M26 174.7a1.7 1.7 0 0 1 2.1-.2 1.7 1.7 0 0 1 .6 2.1 1.64 1.64 0 0 1-2.1 1.2 1.64 1.64 0 0 1-1-2.2zM26.4 174.9a1.56 1.56 0 0 0 .5 2.5 1.35 1.35 0 0 0 1.3-.6 1.35 1.35 0 0 0 0-1.4 1.14 1.14 0 0 0-1.8-.5z"/>
<path d="M33 168.4h1.1a1.74 1.74 0 0 1 1.7 1.8 1.74 1.74 0 0 1-1.8 1.7h-1zM33.4 168.8v2.7h.5a1.37 1.37 0 0 0 1.4-1.3 1.37 1.37 0 0 0-1.3-1.4z"/>
<path d="M40.9 168.4h.9a1.1 1.1 0 0 1 1.3 1.1 1.1 1.1 0 0 1-1.4 1.1h-.4v1.3h-.4zM41.3 168.8v1.4a.94 .94 0 0 0 1.4-.7 .7 .7 0 0 0-.9-.7z"/>
<path d="M45.7 174.7a1.7 1.7 0 0 1 2.2-.2 1.7 1.7 0 0 1 .6 2.1 1.64 1.64 0 0 1-2.1 1.2 1.64 1.64 0 0 1-1.1-2.2zM46.1 174.9a1.56 1.56 0 0 0 .6 2.5 1.35 1.35 0 0 0 1.2-.6 1.35 1.35 0 0 0 .1-1.4 1.14 1.14 0 0 0-1.9-.5z"/>
<path d="M47.3 168.4h.4l1.3 3.5h-.4l-.4-1.1h-1.4l-.4 1.1h-.5zM47.5 168.9l-.6 1.5h1.1z"/>
<path d="M49.3 174.3h1a1 1 0 0 1 1.2 .7 1 1 0 0 1-.7 1.2l1 1.6h-.5l-.9-1.4h-.7v1.4h-.4zM49.7 174.7v1.3h.6a.67 .67 0 0 0 .8-.7 .67 .67 0 0 0-.9-.6z"/>
<path d="M143.9 169.4a1.16 1.16 0 0 1 1.4-.1 1.16 1.16 0 0 1 .5 1.2 1.69 1.69 0 0 1-1 2.2 1.27 1.27 0 0 1-1.3-1.6l.1-1.2zM144.2 169.7a2.16 2.16 0 0 0 .3 2.6 .82 .82 0 0 0 .9-1.1 1.35 1.35 0 0 0-.7-1.7z"/>
<path d="M120 187.4h1a.94 .94 0 0 1 1 .2 .94 .94 0 0 1 .2 1.1l-.6 .4a.95 .95 0 0 1 .8 1.1 .95 .95 0 0 1-1.2 .7h-1.2zM120.4 189.3v1.3h.7a.66 .66 0 0 0 .8-.7 .66 .66 0 0 0-.8-.6zM120.4 187.8v1.1h.7a.6 .6 0 0 0 .7-.6 .6 .6 0 0 0-.8-.5z"/>
<path d="M148.2 187.4h1a1 1 0 0 1 1.2 .7 1 1 0 0 1-.6 1.3l.9 1.5h-.5l-.8-1.4h-.7v1.4h-.5zM148.7 187.8v1.3h.5a.67 .67 0 0 0 .8-.7 .67 .67 0 0 0-.8-.6z"/>
<path d="M151.5 187.9a1.7 1.7 0 0 1 2.2-.2 1.7 1.7 0 0 1 .6 2.1 1.64 1.64 0 0 1-2.1 1.1 1.64 1.64 0 0 1-1.1-2.1zM151.9 188a1.56 1.56 0 0 0 .6 2.6 1.35 1.35 0 0 0 1.2-.6 1.35 1.35 0 0 0 .1-1.4 1.14 1.14 0 0 0-1.9-.6z"/>
<path d="M160.8 187.4h1a.94 .94 0 0 1 1 .2 .94 .94 0 0 1 .2 1.1l-.5 .4a.95 .95 0 0 1 .7 1.1 .95 .95 0 0 1-1.2 .7h-1.2zM161.2 189.3v1.3h.7a.66 .66 0 0 0 .9-.7 .66 .66 0 0 0-.9-.6zM161.2 187.8v1.1h.7a.6 .6 0 0 0 .8-.6 .6 .6 0 0 0-.9-.5z"/>
<path d="M164.9 187.4h.4l1.3 3.5h-.4l-.5-1.1h-1.3l-.5 1.1h-.4zM165 187.9l-.5 1.6h1.1z"/>
<circle cx="279.9" cy="118.9" r=".31"/>
<circle cx="124.6" cy="190.7" r=".31"/>
<circle cx="124.6" cy="188.6" r=".32"/>
</g>
<g fill="none" stroke="#000" stroke-width=".21">
<path d="M144.7 47v4.1M144.7 52.3v1.3M144.7 54.8v6.3M144.7 62.3v1.3M144.7 64.8v6.3M144.7 72.3v1.3M144.7 74.8v6.3M144.7 82.3v1.3M144.7 84.8v6.3M144.7 92.3v1.3M144.7 94.8v6.3M144.7 102.3v1.3"/>
<path d="M144.7 104.8v6.3M144.7 112.3v1.3M144.7 114.8v6.3M144.7 122.3v1.3M144.7 124.8v6.3M144.7 132.3v1.3M144.7 134.8v6.3M144.7 142.3v1.3M144.7 144.8v6.3M144.7 152.3v1.3M144.7 154.8v4.1"/>
</g>
<g fill="#000" stroke="#000" stroke-width=".21">
<path d="M214.1 52.3l.8 .4-1.4 2.1zM54.4 75.3l.6-.6 1.3 2.2zM54.5 68.9l.8-.3 .3 2.5zM211.4 73.8l1.5 2-2.1-1.4zM280.9 61.6l.4 2.5h-.8zM280.5 79.1h.8l-.4 2.5zM280.9 81.6l.4 2.5h-.8zM70.3 122.1l-.4 2.5-.8-.2zM263.2 124.6l.4 2.5h-.8zM262.8 149.1h.8l-.4 2.5zM280.5 153.9h.8l-.4 2.5zM92.2 173.3l2.5-.4v.8z"/>
<path d="M194.7 172.9l2.5 .4-2.5 .4z"/>
</g>
<path d="M139.2 35.1h32.7l41 40.7M8.5 59.7h43.6l3.5 11.4M290 43.8h-71.9l-4.6 11M18.4 69.4h31.4l6.5 7.5M70.3 122.1l-17.3 56.4h-36.2" fill="none" stroke="#000" stroke-width=".25"/>
<path d="M212.3 61.6h69.8M280.9 64.1v15M197.8 81.6h84.3M280.9 84.1v69.8M246.8 124.6h17.7M263.2 127.1v22M92.2 157v17.6M197.2 157v17.6M213.3 151.6h51.2M235.7 156.4h46.4M94.7 173.3h100" fill="none" stroke="#000" stroke-width=".21"/>
<g fill="none" stroke="#000" stroke-width=".21">
<path d="M94.7 50v7.1M94.7 58.4v1.2M194.7 50v7.1M194.7 58.4v1.2M94.7 60.9v6.2M94.7 68.4v1.2M94.7 70.9v6.2M94.7 78.4v1.2M194.7 60.9v6.2M194.7 68.4v1.2M194.7 70.9v6.2M194.7 78.4v1.2"/>
<path d="M94.7 80.9v6.2M94.7 88.4v1.2M94.7 90.9v7.1M94.7 99.2v2.5M194.7 80.9v6.2M194.7 88.4v1.2M194.7 90.9v7.1M194.7 99.2v2.5M44.3 100.5h7.1M52.6 100.5h1.3M55.1 100.5h6.3M62.6 100.5h1.3"/>
<path d="M65.1 100.5h6.3M72.6 100.5h1.3M75.1 100.5h6.3M82.6 100.5h1.3M85.1 100.5h7.1M93.5 100.5h2.5M94.7 103v7M94.7 111.3v1.2M94.7 113.8v6.2M97.2 100.5h7.1M105.6 100.5h1.2M108.1 100.5h6.2"/>
<path d="M115.6 100.5h1.2M118.1 100.5h6.2M125.6 100.5h1.2M128.1 100.5h6.2M135.6 100.5h1.2M138.1 100.5h13.3M152.6 100.5h1.3M155.1 100.5h6.3M162.6 100.5h1.3M165.1 100.5h6.3M172.6 100.5h1.3M175.1 100.5h6.3"/>
<path d="M182.6 100.5h1.3M185.1 100.5h7.1M193.5 100.5h2.5M194.7 103v7M194.7 111.3v1.2M194.7 113.8v6.2M197.2 100.5h7.1M205.6 100.5h1.2M208.1 100.5h6.2M215.6 100.5h1.2M218.1 100.5h6.2M225.6 100.5h1.2"/>
<path d="M228.1 100.5h6.2M235.6 100.5h1.2M238.1 100.5h7.1M94.7 121.3v1.2M94.7 123.8v6.2M94.7 131.3v1.2M94.7 133.8v6.2M194.7 121.3v1.2M194.7 123.8v6.2M194.7 131.3v1.2M194.7 133.8v6.2M94.7 141.3v1.2"/>
<path d="M94.7 143.8v7.1M194.7 141.3v1.2M194.7 143.8v7.1"/>
</g>
</svg>
